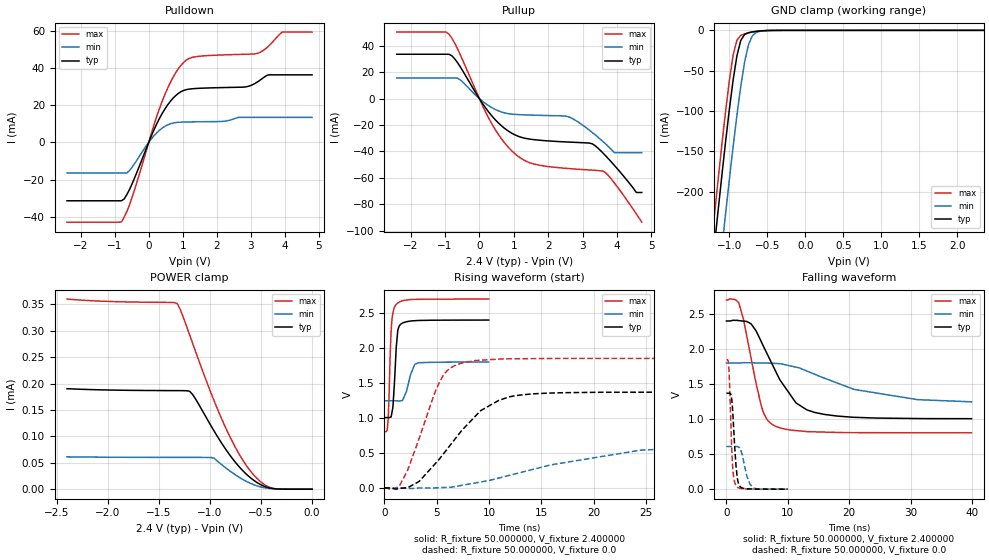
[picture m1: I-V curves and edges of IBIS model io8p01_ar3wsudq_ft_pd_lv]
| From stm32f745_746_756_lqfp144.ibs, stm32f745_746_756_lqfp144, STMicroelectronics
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|   Model io8p01_ar3wsudq_ft_pd_lv
[Model]  io8p01_ar3wsudq_ft_pd_lv
Model_type I/O
Polarity   Non-Inverting
Enable   Active-Low
Vinl =   0.720000V
Vinh =   1.680000V
Vmeas =  1.200000V
Cref =   50.000000pF
Rref =   100.000000M
Vref =   0.0V
C_comp   3.720900pF   3.684200pF   3.822900pF
[Temperature Range]   25.000000   0.125000k   -40.000000
[Pullup Reference]   2.400000V   1.800000V   2.700000V
[Pulldown Reference]   0.0V   0.0V   0.0V
[POWER Clamp Reference]   2.400000V   1.800000V   2.700000V
[GND Clamp Reference]   0.0V   0.0V   0.0V
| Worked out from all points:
|   slope of the pulldown table from 0 to 0.36 V, typ, clamps not added: 25 ohm
|   slope of the pullup table from 0 to 0.36 V, typ, clamps not added: 27.7 ohm
|   GND clamp passes 1 mA (typ) near -0.62 V on its own axis
|   rising waveform, R_fixture 50.000000, V_fixture 2.400000: 20-80 % time 332ps typ, 645ps min, 264ps max; typ from 1 V to 2.4 V
|   rising waveform, R_fixture 50.000000, V_fixture 0.0: 20-80 % time 4.73ns typ, 11.9ns min, 2.67ns max; typ from 0 V to 1.37 V
|   falling waveform, R_fixture 50.000000, V_fixture 2.400000: 20-80 % time 5.31ns typ, 12.5ns min, 2.7ns max; typ from 2.4 V to 1 V
|   falling waveform, R_fixture 50.000000, V_fixture 0.0: 20-80 % time 592ps typ, 1.02ns min, 460ps max; typ from 1.37 V to 0 V
[Pulldown]
|Voltage   I(typ)   I(min)   I(max)
-2.4V     -31.47mA   -16.45mA   -43.01mA
-800mV    -31.47mA   -16.45mA   -42.85mA
-480mV    -21.98mA   -13.17mA   -29.2mA
80mV      3.63mA     1.966mA    5.014mA
480mV     18.15mA    8.738mA    26.02mA
800mV     25.38mA    10.72mA    37.77mA
1.12V     28.53mA    11.02mA    44.6mA
2.8V      29.84mA    13.51mA    47.53mA
3.2V      32.66mA    13.51mA    48.04mA
3.52V     36.44mA    13.51mA    51.84mA
3.92V     36.44mA    13.51mA    59.49mA
4.8V      36.44mA    13.51mA    59.49mA
[Pullup]
|Voltage   I(typ)   I(min)   I(max)
-2.4V     33.58mA    15.57mA    50.36mA
-960mV    33.58mA    15.57mA    50.36mA
-560mV    24.28mA    14.31mA    33.53mA
320mV     -11.75mA   -6.207mA   -17.08mA
960mV     -26.47mA   -11.82mA   -40.02mA
1.52V     -30.88mA   -12.51mA   -49.05mA
2.56V     -32.88mA   -13.52mA   -52.9mA
3.28V     -34.25mA   -25.64mA   -54.18mA
3.6V      -41.44mA   -32.74mA   -55.03mA
3.92V     -50.46mA   -40.9mA    -63.79mA
4.56V     -71.1mA    -40.9mA    -87.27mA
4.72V     -71.1mA    -40.9mA    -93.6mA
[GND_clamp]
|Voltage   I(typ)   I(min)   I(max)
-2.4V     -1.429A    -1.514A    -1.399A
-1.25V    -315.9mA   -407.2mA   -278.2mA
-1.2V     -270.1mA   -361.3mA   -232.1mA
-1.15V    -225mA     -316mA     -186.8mA
-1.1V     -180.9mA   -271.3mA   -142.7mA
-1.05V    -138.2mA   -227.5mA   -100.5mA
-950mV    -61.14mA   -143.6mA   -30.44mA
-900mV    -31.24mA   -104.7mA   -12.15mA
-850mV    -12.5mA    -69.41mA   -6.236mA
-750mV    -2.91mA    -18.35mA   -3.195mA
-600mV    -761.5uA   -1.227mA   -751.9uA
2.35V     58.09uA    37.93uA    67.25uA
[POWER_clamp]
|Voltage   I(typ)   I(min)   I(max)
-2.4V     190.2uA    61.19uA    359.9uA
-1.32V    186.6uA    60.14uA    351.2uA
-1.29V    186.5uA    60.13uA    339.6uA
-1.2V     185.4uA    60.11uA    292.6uA
-1.17V    179.2uA    60.11uA    276.3uA
-960mV    110.2uA    58.62uA    167.5uA
-870mV    82.44uA    43.99uA    126.3uA
-750mV    50.58uA    26.92uA    78.64uA
-630mV    25.94uA    13.41uA    41.02uA
-510mV    9.22uA     4.527uA    14.97uA
-420mV    2.425uA    1.38uA     3.75uA
0V        0A         0A         0A
[Ramp]
| variable   typ   min   max
dV/dt_r  0.82164/4.72408n   0.36480/11.89880n   1.11048/2.66440n
dV/dt_f  0.83676/5.31772n   0.32370/13.40985n   1.13680/2.70151n
R_load = 50.000000
[Rising Waveform]
R_fixture= 50.000000
V_fixture= 2.400000
V_fixture_min= 1.800000
V_fixture_max= 2.700000
|time   V(typ)   V(min)   V(max)
0s        1.005V     1.245V     804.3mV
340.3ps   1.005V     1.245V     950.4mV
640.6ps   1.018V     1.246V     2.26V
820.8ps   1.187V     1.246V     2.509V
1.081ns   1.882V     1.245V     2.616V
1.281ns   2.258V     1.245V     2.644V
1.802ns   2.361V     1.277V     2.678V
2.883ns   2.389V     1.762V     2.694V
3.263ns   2.393V     1.79V      2.695V
9.97ns    2.399V     1.799V     2.699V
[Rising Waveform]
R_fixture= 50.000000
V_fixture= 0.0
V_fixture_min= 0.0
V_fixture_max= 0.0
|time   V(typ)   V(min)   V(max)
0s        177.8uV    72.94uV    448.7uV
1.522ns   -4.552mV   139.8uV    54.49mV
3.283ns   91.27mV    -1.145mV   692.9mV
5.205ns   404.8mV    3.699mV    1.495V
6.086ns   573mV      9.565mV    1.687V
7.367ns   817.9mV    37.03mV    1.783V
9.209ns   1.105V     85.57mV    1.825V
13.13ns   1.33V      225.2mV    1.847V
24.5ns    1.368V     540.2mV    1.851V
39.88ns   1.369V     608.4mV    1.851V
[Falling Waveform]
R_fixture= 50.000000
V_fixture= 2.400000
V_fixture_min= 1.800000
V_fixture_max= 2.700000
|time   V(typ)   V(min)   V(max)
0s        2.399V     1.799V     2.699V
2.002ns   2.405V     1.8V       2.661V
2.803ns   2.397V     1.804V     2.409V
4.004ns   2.359V     1.803V     1.873V
5.846ns   2.07V      1.798V     1.137V
7.768ns   1.724V     1.794V     907.1mV
11.29ns   1.234V     1.741V     835.8mV
14.33ns   1.095V     1.64V      817.7mV
20.82ns   1.025V     1.422V     806.7mV
39.88ns   1.005V     1.245V     804.3mV
[Falling Waveform]
R_fixture= 50.000000
V_fixture= 0.0
V_fixture_min= 0.0
V_fixture_max= 0.0
|time   V(typ)   V(min)   V(max)
0s        1.369V     608.4mV    1.851V
380.4ps   1.369V     608.4mV    1.735V
880.9ps   1.272V     608.2mV    540.9mV
1.121ns   954mV      607.9mV    208mV
1.481ns   427.8mV    608.6mV    63.82mV
1.762ns   164.3mV    608.4mV    30.4mV
2.122ns   49.87mV    592.3mV    14.87mV
3.323ns   5.318mV    185.8mV    2.808mV
4.505ns   1.963mV    13.35mV    1.375mV
9.97ns    177.8uV    72.94uV    448.7uV
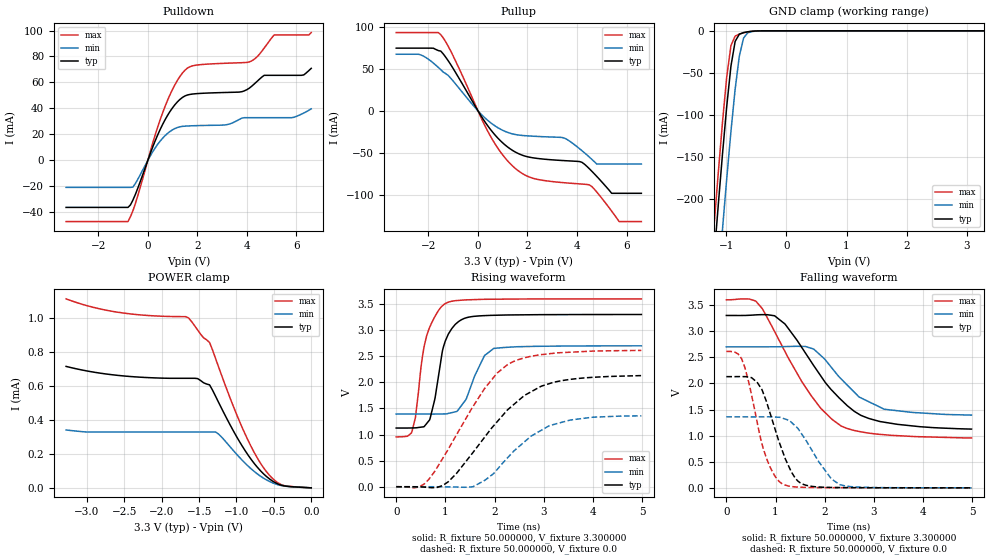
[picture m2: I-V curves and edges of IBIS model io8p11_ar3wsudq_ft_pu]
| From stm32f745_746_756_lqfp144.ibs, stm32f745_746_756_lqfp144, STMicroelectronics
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|   Model io8p11_ar3wsudq_ft_pu
[Model]  io8p11_ar3wsudq_ft_pu
Model_type I/O
Polarity   Non-Inverting
Enable   Active-Low
Vinl =   0.990000V
Vinh =   2.310000V
Vmeas =  1.650000V
Cref =   30.000000pF
Rref =   100.000000M
Vref =   0.0V
C_comp   3.843200pF   3.761700pF   3.937000pF
[Temperature Range]   25.000000   0.125000k   -40.000000
[Pullup Reference]   3.300000V   2.700000V   3.600000V
[Pulldown Reference]   0.0V   0.0V   0.0V
[POWER Clamp Reference]   3.300000V   2.700000V   3.600000V
[GND Clamp Reference]   0.0V   0.0V   0.0V
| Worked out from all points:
|   slope of the pulldown table from 0 to 0.495 V, typ, clamps not added: 20.9 ohm
|   slope of the pullup table from 0 to 0.495 V, typ, clamps not added: 22.6 ohm
|   GND clamp passes 1 mA (typ) near -0.62 V on its own axis
|   rising waveform, R_fixture 50.000000, V_fixture 3.300000: 20-80 % time 277ps typ, 352ps min, 277ps max; typ from 1.12 V to 3.3 V
|   rising waveform, R_fixture 50.000000, V_fixture 0.0: 20-80 % time 1.18ns typ, 961ps min, 1.04ns max; typ from 0.001 V to 2.13 V
|   falling waveform, R_fixture 50.000000, V_fixture 3.300000: 20-80 % time 1.07ns typ, 863ps min, 1.02ns max; typ from 3.3 V to 1.12 V
|   falling waveform, R_fixture 50.000000, V_fixture 0.0: 20-80 % time 466ps typ, 565ps min, 398ps max; typ from 2.13 V to 0.001 V
[Pulldown]
|Voltage   I(typ)   I(min)   I(max)
-3.3V     -36.18mA   -20.77mA   -47.07mA
-800mV    -36.18mA   -20.77mA   -47.07mA
-600mV    -30.5mA    -20.52mA   -38.69mA
700mV     31.4mA     19.11mA    41.71mA
1.2V      45.15mA    25.37mA    61.75mA
1.6V      50.35mA    26.5mA     71.06mA
3.1V      52.28mA    27.26mA    74.76mA
4.1V      55.65mA    32.89mA    75.79mA
4.7V      65.5mA     32.89mA    86.49mA
5.1V      65.5mA     32.89mA    96.55mA
6.3V      65.83mA    36.49mA    96.55mA
6.6V      70.88mA    39.7mA     98.4mA
[Pullup]
|Voltage   I(typ)   I(min)   I(max)
-3.3V     74.71mA    67.42mA    93.28mA
-2.3V     74.71mA    66.58mA    93.28mA
-1.5V     71.15mA    49mA       90.77mA
-1V       50.42mA    35.45mA    65.35mA
500mV     -22.06mA   -14mA      -30.03mA
1.6V      -50.64mA   -28.81mA   -70.96mA
3.5V      -59.52mA   -32.72mA   -85.91mA
4.5V      -69.2mA    -55.26mA   -88.43mA
4.8V      -78.36mA   -63.6mA    -97mA
5.4V      -98.5mA    -63.6mA    -119.7mA
5.7V      -98.5mA    -63.6mA    -132.2mA
6.6V      -98.5mA    -63.6mA    -132.2mA
[GND_clamp]
|Voltage   I(typ)   I(min)   I(max)
-3.3V     -2.325A    -2.404A    -2.299A
-1.2V     -270.2mA   -361.4mA   -232.1mA
-1.13V    -207.3mA   -298.1mA   -169mA
-1.06V    -146.7mA   -236.2mA   -108.8mA
-990mV    -90.18mA   -176.4mA   -54.96mA
-920mV    -42.21mA   -120mA     -17.68mA
-850mV    -12.57mA   -69.47mA   -6.265mA
-780mV    -3.971mA   -30.01mA   -3.886mA
-710mV    -2.1mA     -8.615mA   -2.382mA
-640mV    -1.148mA   -2.283mA   -1.22mA
-570mV    -524uA     -821.5uA   -476.8uA
3.28V     0A         0A         0A
[POWER_clamp]
|Voltage   I(typ)   I(min)   I(max)
-3.28V    715.1uA    340.8uA    1.113mA
-2.6V     662.9uA    328.8uA    1.035mA
-1.64V    645uA      328.8uA    1mA
-1.52V    643.3uA    328.8uA    929.5uA
-1.36V    606.3uA    328.8uA    855.6uA
-1.24V    503.7uA    316.8uA    712.3uA
-960mV    272.5uA    179.4uA    391.9uA
-800mV    165.1uA    110.4uA    239.2uA
-640mV    83.2uA     57.57uA    119.3uA
-520mV    40.52uA    29.83uA    56.09uA
-400mV    15.54uA    13.29uA    18.7uA
0V        0A         0A         0A
[Ramp]
| variable   typ   min   max
dV/dt_r  1.25875/1.16604n   0.80019/0.94572n   1.56010/1.04197n
dV/dt_f  1.27428/1.04940n   0.76752/0.84517n   1.56854/1.01586n
R_load = 50.000000
[Rising Waveform]
R_fixture= 50.000000
V_fixture= 3.300000
V_fixture_min= 2.700000
V_fixture_max= 3.600000
|time   V(typ)   V(min)   V(max)
0s        1.125V     1.393V     955.6mV
320.3ps   1.127V     1.393V     1.057V
390.4ps   1.129V     1.393V     1.326V
560.6ps   1.149V     1.393V     2.647V
680.7ps   1.283V     1.393V     3.056V
1.011ns   2.82V      1.396V     3.515V
1.421ns   3.236V     1.676V     3.58V
1.792ns   3.278V     2.507V     3.591V
1.982ns   3.284V     2.649V     3.592V
4.985ns   3.3V       2.7V       3.599V
[Rising Waveform]
R_fixture= 50.000000
V_fixture= 0.0
V_fixture_min= 0.0
V_fixture_max= 0.0
|time   V(typ)   V(min)   V(max)
0s        1.433mV    1.239mV    1.787mV
570.6ps   -6.138mV   1.229mV    54.34mV
840.8ps   -9.86mV    894.5uV    382.8mV
1.061ns   98.44mV    -1.345mV   725.5mV
1.562ns   658.1mV    1.247mV    1.537V
2.052ns   1.246V     330.3mV    2.178V
2.352ns   1.545V     645mV      2.385V
3.113ns   1.976V     1.17V      2.548V
3.994ns   2.097V     1.333V     2.599V
4.985ns   2.129V     1.359V     2.612V
[Falling Waveform]
R_fixture= 50.000000
V_fixture= 3.300000
V_fixture_min= 2.700000
V_fixture_max= 3.600000
|time   V(typ)   V(min)   V(max)
0s        3.3V       2.7V       3.599V
600.6ps   3.311V     2.7V       3.573V
740.7ps   3.316V     2.7V       3.416V
981ps     3.294V     2.701V     2.994V
1.201ns   3.126V     2.704V     2.594V
1.772ns   2.347V     2.659V     1.708V
2.332ns   1.688V     2.088V     1.186V
2.703ns   1.407V     1.738V     1.08V
3.213ns   1.257V     1.505V     1.017V
4.985ns   1.125V     1.393V     955.6mV
[Falling Waveform]
R_fixture= 50.000000
V_fixture= 0.0
V_fixture_min= 0.0
V_fixture_max= 0.0
|time   V(typ)   V(min)   V(max)
0s        2.129V     1.359V     2.612V
310.3ps   2.13V      1.359V     2.473V
470.5ps   2.117V     1.359V     1.965V
630.6ps   2.016V     1.359V     1.24V
880.9ps   1.456V     1.36V      416mV
1.131ns   731.6mV    1.339V     83.11mV
1.502ns   97.45mV    1.075V     13.98mV
2.132ns   8.951mV    176.6mV    4.432mV
2.312ns   6.693mV    61.01mV    4.047mV
4.985ns   1.433mV    1.239mV    1.787mV
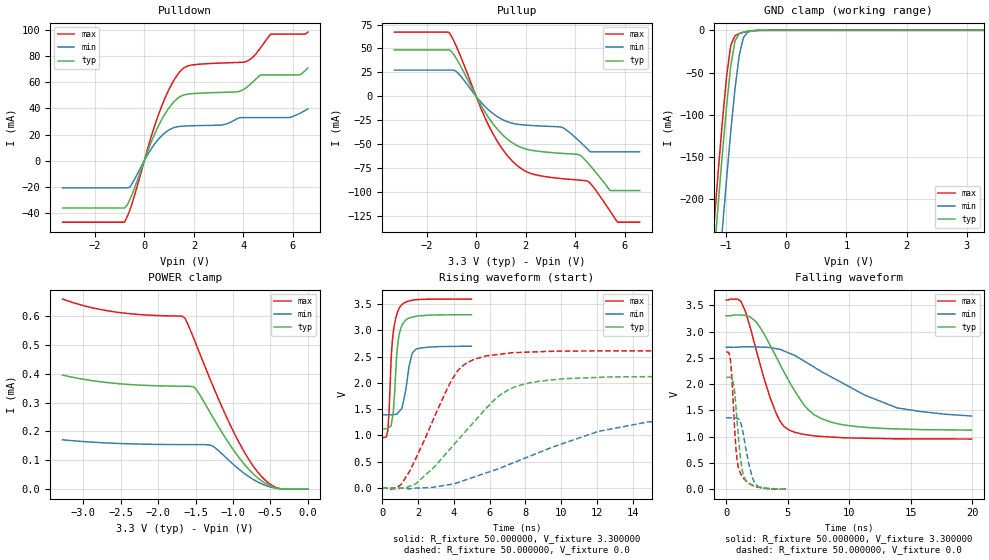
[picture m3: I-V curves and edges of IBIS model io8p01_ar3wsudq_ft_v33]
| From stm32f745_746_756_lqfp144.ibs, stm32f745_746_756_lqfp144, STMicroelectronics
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|   Model io8p01_ar3wsudq_ft_v33
[Model]  io8p01_ar3wsudq_ft_v33
Model_type I/O
Polarity   Non-Inverting
Enable   Active-Low
Vinl =   0.990000V
Vinh =   2.310000V
Vmeas =  1.650000V
Cref =   50.000000pF
Rref =   100.000000M
Vref =   0.0V
C_comp   3.857500pF   3.760500pF   3.941700pF
[Temperature Range]   25.000000   0.125000k   -40.000000
[Pullup Reference]   3.300000V   2.700000V   3.600000V
[Pulldown Reference]   0.0V   0.0V   0.0V
[POWER Clamp Reference]   3.300000V   2.700000V   3.600000V
[GND Clamp Reference]   0.0V   0.0V   0.0V
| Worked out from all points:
|   slope of the pulldown table from 0 to 0.495 V, typ, clamps not added: 20.9 ohm
|   slope of the pullup table from 0 to 0.495 V, typ, clamps not added: 22.6 ohm
|   GND clamp passes 1 mA (typ) near -0.62 V on its own axis
|   rising waveform, R_fixture 50.000000, V_fixture 3.300000: 20-80 % time 277ps typ, 398ps min, 275ps max; typ from 1.12 V to 3.3 V
|   rising waveform, R_fixture 50.000000, V_fixture 0.0: 20-80 % time 3.36ns typ, 6.53ns min, 2.12ns max; typ from 0 V to 2.13 V
|   falling waveform, R_fixture 50.000000, V_fixture 3.300000: 20-80 % time 3.2ns typ, 6.4ns min, 2.04ns max; typ from 3.3 V to 1.12 V
|   falling waveform, R_fixture 50.000000, V_fixture 0.0: 20-80 % time 516ps typ, 710ps min, 443ps max; typ from 2.13 V to 0 V
[Pulldown]
|Voltage   I(typ)   I(min)   I(max)
-3.3V     -36.18mA   -20.77mA   -47.07mA
-800mV    -36.18mA   -20.77mA   -47.07mA
-600mV    -30.5mA    -20.52mA   -38.69mA
700mV     31.4mA     19.11mA    41.71mA
1.2V      45.15mA    25.37mA    61.75mA
1.6V      50.35mA    26.5mA     71.06mA
3.1V      52.28mA    27.26mA    74.76mA
4.1V      55.7mA     32.99mA    75.8mA
4.7V      65.72mA    32.99mA    86.64mA
5.1V      65.72mA    32.99mA    96.89mA
6.3V      65.85mA    36.5mA     96.89mA
6.6V      70.91mA    39.71mA    98.45mA
[Pullup]
|Voltage   I(typ)   I(min)   I(max)
-3.3V     48.51mA    27.44mA    67.09mA
-1.1V     48.51mA    27.44mA    66.83mA
-700mV    35.13mA    23.48mA    46.33mA
500mV     -22.07mA   -14mA      -30.03mA
1.5V      -49.1mA    -28.3mA    -68.56mA
2.2V      -56.05mA   -30.32mA   -80.35mA
3.5V      -59.53mA   -32.72mA   -85.92mA
4.2V      -61.52mA   -47.6mA    -87.46mA
4.5V      -69.21mA   -55.15mA   -88.43mA
5.4V      -98.3mA    -57.9mA    -119.4mA
5.7V      -98.3mA    -57.9mA    -131.3mA
6.6V      -98.3mA    -57.9mA    -131.3mA
[GND_clamp]
|Voltage   I(typ)   I(min)   I(max)
-3.3V     -2.333A    -2.407A    -2.313A
-1.2V     -270.2mA   -361.4mA   -232.1mA
-1.13V    -207.3mA   -298.1mA   -169mA
-1.06V    -146.7mA   -236.2mA   -108.8mA
-990mV    -90.18mA   -176.4mA   -54.96mA
-920mV    -42.21mA   -120mA     -17.68mA
-850mV    -12.57mA   -69.47mA   -6.265mA
-780mV    -3.971mA   -30.01mA   -3.886mA
-710mV    -2.1mA     -8.615mA   -2.382mA
-640mV    -1.148mA   -2.283mA   -1.22mA
-570mV    -524uA     -821.5uA   -476.8uA
3.28V     0A         0A         0A
[POWER_clamp]
|Voltage   I(typ)   I(min)   I(max)
-3.28V    395.3uA    171.3uA    658.7uA
-2.6V     367.1uA    159uA      614.9uA
-1.68V    356.7uA    154.4uA    599.4uA
-1.64V    356.5uA    154.4uA    590.8uA
-1.52V    353.6uA    154.3uA    518.3uA
-1.48V    341.1uA    154.2uA    492.3uA
-1.28V    253.6uA    150.4uA    364.2uA
-960mV    123.1uA    77.55uA    181.6uA
-720mV    50.52uA    32.03uA    76.18uA
-560mV    18.94uA    12.27uA    28.65uA
-440mV    5.104uA    3.69uA     7.327uA
0V        0A         0A         0A
[Ramp]
| variable   typ   min   max
dV/dt_r  1.27764/3.35565n   0.80076/6.63242n   1.56720/2.11409n
dV/dt_f  1.30260/3.20700n   0.74268/6.39481n   1.58788/2.03530n
R_load = 50.000000
[Rising Waveform]
R_fixture= 50.000000
V_fixture= 3.300000
V_fixture_min= 2.700000
V_fixture_max= 3.600000
|time   V(typ)   V(min)   V(max)
0s        1.124V     1.392V     954.2mV
320.3ps   1.132V     1.392V     1.099V
390.4ps   1.151V     1.391V     1.455V
510.5ps   1.2V       1.392V     2.477V
650.7ps   1.577V     1.398V     3.035V
830.8ps   2.594V     1.409V     3.315V
991ps     2.979V     1.471V     3.448V
1.682ns   3.255V     2.57V      3.576V
1.882ns   3.269V     2.642V     3.587V
4.985ns   3.3V       2.7V       3.599V
[Rising Waveform]
R_fixture= 50.000000
V_fixture= 0.0
V_fixture_min= 0.0
V_fixture_max= 0.0
|time   V(typ)   V(min)   V(max)
0s        196.4uV    83.4uV     722.1uV
1.041ns   -10.14mV   -4.317mV   56.18mV
1.882ns   78.86mV    -5.015mV   561.1mV
3.844ns   759.6mV    67.51mV    2.031V
5.085ns   1.241V     200.2mV    2.443V
6.567ns   1.765V     373.5mV    2.547V
8.208ns   1.999V     598.4mV    2.588V
12.05ns   2.105V     1.075V     2.61V
14.77ns   2.12V      1.252V     2.612V
19.94ns   2.129V     1.359V     2.612V
[Falling Waveform]
R_fixture= 50.000000
V_fixture= 3.300000
V_fixture_min= 2.700000
V_fixture_max= 3.600000
|time   V(typ)   V(min)   V(max)
0s        3.3V       2.7V       3.599V
1.201ns   3.314V     2.708V     3.573V
2.442ns   3.185V     2.707V     2.647V
3.604ns   2.725V     2.691V     1.723V
4.324ns   2.401V     2.664V     1.315V
5.085ns   2.066V     2.593V     1.131V
6.727ns   1.501V     2.382V     1.029V
8.569ns   1.273V     2.132V     991.8mV
13.89ns   1.147V     1.547V     958.7mV
19.94ns   1.124V     1.392V     954.2mV
[Falling Waveform]
R_fixture= 50.000000
V_fixture= 0.0
V_fixture_min= 0.0
V_fixture_max= 0.0
|time   V(typ)   V(min)   V(max)
0s        2.129V     1.359V     2.612V
340.3ps   2.126V     1.358V     2.474V
500.5ps   2.082V     1.358V     1.97V
640.6ps   1.941V     1.358V     1.363V
890.9ps   1.294V     1.347V     553mV
1.171ns   578.9mV    1.262V     295.9mV
1.512ns   205.7mV    893.9mV    182.2mV
1.852ns   108.4mV    473.4mV    112.1mV
2.312ns   59.63mV    121.3mV    51.33mV
4.985ns   196.4uV    83.4uV     722.1uV
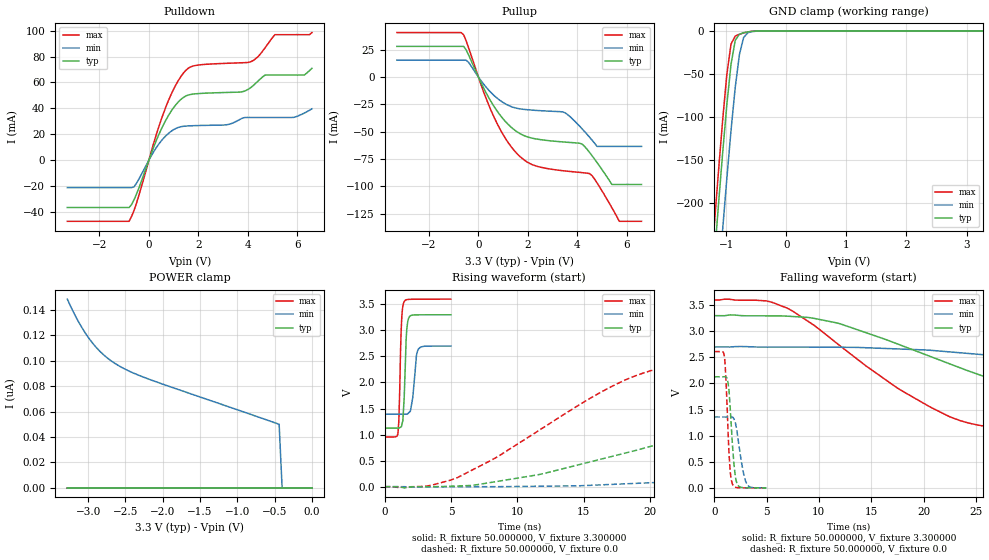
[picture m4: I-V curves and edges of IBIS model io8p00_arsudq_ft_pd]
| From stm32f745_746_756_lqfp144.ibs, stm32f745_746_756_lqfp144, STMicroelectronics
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|   Model io8p00_arsudq_ft_pd
[Model]  io8p00_arsudq_ft_pd
Model_type I/O
Polarity   Non-Inverting
Enable   Active-Low
Vinl =   0.990000V
Vinh =   2.310000V
Vmeas =  1.650000V
Cref =   50.000000pF
Rref =   100.000000M
Vref =   0.0V
C_comp   2.292100pF   2.228000pF   2.366600pF
[Temperature Range]   25.000000   0.125000k   -40.000000
[Pullup Reference]   3.300000V   2.700000V   3.600000V
[Pulldown Reference]   0.0V   0.0V   0.0V
[POWER Clamp Reference]   3.300000V   2.700000V   3.600000V
[GND Clamp Reference]   0.0V   0.0V   0.0V
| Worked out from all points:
|   slope of the pulldown table from 0 to 0.495 V, typ, clamps not added: 20.9 ohm
|   slope of the pullup table from 0 to 0.495 V, typ, clamps not added: 22.6 ohm
|   GND clamp passes 1 mA (typ) near -0.62 V on its own axis
|   rising waveform, R_fixture 50.000000, V_fixture 3.300000: 20-80 % time 190ps typ, 291ps min, 164ps max; typ from 1.12 V to 3.3 V
|   rising waveform, R_fixture 50.000000, V_fixture 0.0: 20-80 % time 19.7ns typ, 51ns min, 10.4ns max; typ from 0 V to 2.13 V
|   falling waveform, R_fixture 50.000000, V_fixture 3.300000: 20-80 % time 18.7ns typ, 39.7ns min, 11.5ns max; typ from 3.3 V to 1.12 V
|   falling waveform, R_fixture 50.000000, V_fixture 0.0: 20-80 % time 433ps typ, 632ps min, 343ps max; typ from 2.13 V to 0 V
[Pulldown]
|Voltage   I(typ)   I(min)   I(max)
-3.3V     -36.46mA   -21.1mA    -47.09mA
-800mV    -36.46mA   -21.1mA    -47.09mA
-600mV    -30.5mA    -20.54mA   -38.69mA
700mV     31.4mA     19.11mA    41.71mA
1.2V      45.15mA    25.37mA    61.75mA
1.6V      50.35mA    26.5mA     71.06mA
3.1V      52.27mA    27.26mA    74.75mA
4.1V      55.7mA     32.99mA    75.8mA
4.7V      65.72mA    32.99mA    86.69mA
5.1V      65.72mA    32.99mA    96.9mA
6.3V      65.87mA    36.5mA     96.9mA
6.6V      70.93mA    39.71mA    98.5mA
[Pullup]
|Voltage   I(typ)   I(min)   I(max)
-3.3V     28.03mA    15.43mA    40.69mA
-700mV    28.03mA    15.43mA    40.69mA
-400mV    20.31mA    13.47mA    26.93mA
600mV     -25.77mA   -16.23mA   -35.13mA
1.6V      -50.64mA   -28.81mA   -70.96mA
3.5V      -59.53mA   -32.65mA   -85.92mA
4.2V      -61.43mA   -47.49mA   -87.46mA
4.5V      -69.06mA   -55.12mA   -88.38mA
4.8V      -78.23mA   -63.5mA    -96.83mA
5.4V      -98.3mA    -63.5mA    -119.6mA
5.7V      -98.3mA    -63.5mA    -132mA
6.6V      -98.3mA    -63.5mA    -132mA
[GND_clamp]
|Voltage   I(typ)   I(min)   I(max)
-3.3V     -2.318A    -2.397A    -2.291A
-1.2V     -265.5mA   -356.1mA   -227.2mA
-1.13V    -202.7mA   -292.9mA   -164.1mA
-1.06V    -142.2mA   -231.2mA   -104.1mA
-990mV    -85.98mA   -171.6mA   -50.73mA
-920mV    -38.81mA   -115.5mA   -15.29mA
-850mV    -11.09mA   -65.61mA   -6.016mA
-780mV    -3.793mA   -27.42mA   -3.89mA
-710mV    -2.098mA   -7.698mA   -2.396mA
-640mV    -1.159mA   -2.127mA   -1.234mA
-570mV    -535.1uA   -807.4uA   -490.2uA
3.28V     81.28uA    57.87uA    93.98uA
[POWER_clamp]
|Voltage   I(typ)   I(min)   I(max)
-3.28V    0A         148.5nA    0A
-3.2V     0A         138.6nA    0A
-3.12V    0A         129.7nA    0A
-3.04V    0A         122nA      0A
-2.96V    0A         115.3nA    0A
-2.8V     0A         105.1nA    0A
-2.6V     0A         96.44nA    0A
-2.4V     0A         90.52nA    0A
-2.16V    0A         84.97nA    0A
-440mV    0A         50.04nA    0A
-400mV    0A         0A         0A
0V        0A         0A         0A
[Ramp]
| variable   typ   min   max
dV/dt_r  1.27668/19.69888n   0.81474/51.01036n   1.56654/10.33703n
dV/dt_f  1.30626/18.72002n   0.78504/39.74867n   1.58742/11.43997n
R_load = 50.000000
[Rising Waveform]
R_fixture= 50.000000
V_fixture= 3.300000
V_fixture_min= 2.700000
V_fixture_max= 3.600000
|time   V(typ)   V(min)   V(max)
0s        1.123V     1.39V      953.1mV
1.001ns   1.125V     1.391V     1.018V
1.071ns   1.127V     1.391V     1.288V
1.251ns   1.148V     1.391V     3.036V
1.461ns   1.66V      1.389V     3.544V
1.632ns   2.883V     1.392V     3.587V
1.862ns   3.26V      1.429V     3.595V
2.112ns   3.293V     1.702V     3.596V
2.533ns   3.297V     2.64V      3.597V
4.985ns   3.299V     2.699V     3.599V
[Rising Waveform]
R_fixture= 50.000000
V_fixture= 0.0
V_fixture_min= 0.0
V_fixture_max= 0.0
|time   V(typ)   V(min)   V(max)
0s        4.821nV    241.3nV    3.051nV
5.506ns   13.81mV    -140.1uV   177.6mV
11.51ns   227.3mV    8.249mV    1.063V
19.02ns   703.2mV    64.82mV    2.14V
27.53ns   1.298V     163.3mV    2.486V
38.54ns   1.853V     359.9mV    2.575V
57.56ns   2.067V     709.4mV    2.607V
89.09ns   2.118V     1.138V     2.611V
117.6ns   2.127V     1.297V     2.611V
249.2ns   2.128V     1.358V     2.611V
[Falling Waveform]
R_fixture= 50.000000
V_fixture= 3.300000
V_fixture_min= 2.700000
V_fixture_max= 3.600000
|time   V(typ)   V(min)   V(max)
0s        3.299V     2.699V     3.599V
5.506ns   3.295V     2.697V     3.556V
12.01ns   3.144V     2.693V     2.722V
22.52ns   2.374V     2.604V     1.36V
31.53ns   1.731V     2.431V     1.073V
39.54ns   1.388V     2.238V     1.016V
47.05ns   1.269V     2.052V     996.2mV
62.56ns   1.185V     1.738V     969.4mV
90.59ns   1.142V     1.509V     955.7mV
249.2ns   1.123V     1.39V      953.1mV
[Falling Waveform]
R_fixture= 50.000000
V_fixture= 0.0
V_fixture_min= 0.0
V_fixture_max= 0.0
|time   V(typ)   V(min)   V(max)
0s        2.128V     1.358V     2.611V
981ps     2.129V     1.357V     2.506V
1.151ns   2.119V     1.357V     1.945V
1.411ns   1.869V     1.358V     683.7mV
1.542ns   1.488V     1.36V      294.8mV
1.742ns   830.7mV    1.353V     75.43mV
2.152ns   98.77mV    1.119V     6.562mV
2.833ns   3.156mV    244.5mV    111.1uV
3.123ns   849.3uV    72.11mV    77.11uV
4.985ns   4.821nV    241.3nV    3.051nV
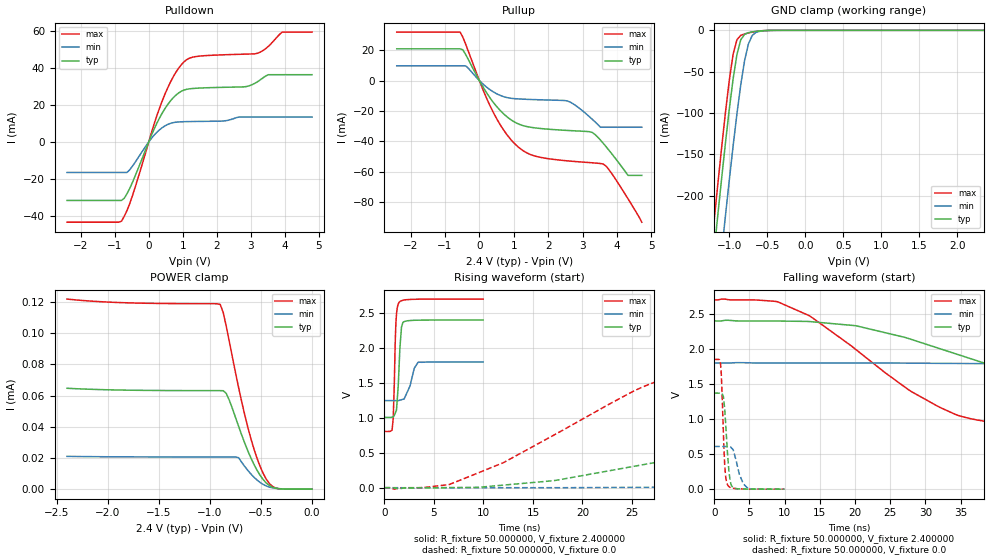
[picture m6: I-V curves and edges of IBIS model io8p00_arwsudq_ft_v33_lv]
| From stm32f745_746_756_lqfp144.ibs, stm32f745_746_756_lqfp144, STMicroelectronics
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|   Model io8p00_arwsudq_ft_v33_lv
[Model]  io8p00_arwsudq_ft_v33_lv
Model_type I/O
Polarity   Non-Inverting
Enable   Active-Low
Vinl =   0.720000V
Vinh =   1.680000V
Vmeas =  1.200000V
Cref =   50.000000pF
Rref =   100.000000M
Vref =   0.0V
C_comp   2.828400pF   2.771400pF   2.910300pF
[Temperature Range]   25.000000   0.125000k   -40.000000
[Pullup Reference]   2.400000V   1.800000V   2.700000V
[Pulldown Reference]   0.0V   0.0V   0.0V
[POWER Clamp Reference]   2.400000V   1.800000V   2.700000V
[GND Clamp Reference]   0.0V   0.0V   0.0V
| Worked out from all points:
|   slope of the pulldown table from 0 to 0.36 V, typ, clamps not added: 25 ohm
|   slope of the pullup table from 0 to 0.36 V, typ, clamps not added: 27.7 ohm
|   GND clamp passes 1 mA (typ) near -0.62 V on its own axis
|   rising waveform, R_fixture 50.000000, V_fixture 2.400000: 20-80 % time 323ps typ, 710ps min, 219ps max; typ from 1.01 V to 2.4 V
|   rising waveform, R_fixture 50.000000, V_fixture 0.0: 20-80 % time 30.9ns typ, 81.7ns min, 14.6ns max; typ from 0 V to 1.37 V
|   falling waveform, R_fixture 50.000000, V_fixture 2.400000: 20-80 % time 28.7ns typ, 81.4ns min, 16.1ns max; typ from 2.4 V to 1.01 V
|   falling waveform, R_fixture 50.000000, V_fixture 0.0: 20-80 % time 552ps typ, 1.05ns min, 408ps max; typ from 1.37 V to 0 V
[Pulldown]
|Voltage   I(typ)   I(min)   I(max)
-2.4V     -31.66mA   -16.51mA   -43.43mA
-800mV    -31.66mA   -16.51mA   -42.86mA
-480mV    -21.98mA   -13.17mA   -29.21mA
80mV      3.63mA     1.966mA    5.014mA
480mV     18.16mA    8.738mA    26.02mA
800mV     25.38mA    10.72mA    37.77mA
1.12V     28.53mA    11.02mA    44.6mA
2.8V      29.84mA    13.48mA    47.53mA
3.2V      32.65mA    13.48mA    48.04mA
3.52V     36.42mA    13.48mA    51.83mA
3.92V     36.42mA    13.48mA    59.49mA
4.8V      36.42mA    13.48mA    59.49mA
[Pullup]
|Voltage   I(typ)   I(min)   I(max)
-2.4V     20.89mA    9.661mA    31.89mA
-560mV    20.89mA    9.661mA    31.89mA
-400mV    17.28mA    9.661mA    24.06mA
320mV     -11.75mA   -6.207mA   -17.08mA
640mV     -20.52mA   -10.1mA    -30.35mA
960mV     -26.47mA   -11.82mA   -40.02mA
1.52V     -30.88mA   -12.51mA   -49.05mA
2.56V     -32.88mA   -13.49mA   -52.9mA
3.28V     -34.2mA    -25.51mA   -54.18mA
3.6V      -41.34mA   -30.77mA   -55mA
4.32V     -62.48mA   -30.77mA   -77.88mA
4.72V     -62.48mA   -30.77mA   -93.3mA
[GND_clamp]
|Voltage   I(typ)   I(min)   I(max)
-2.4V     -1.428A    -1.51A     -1.401A
-1.2V     -266.4mA   -356.3mA   -229.4mA
-1.15V    -221.3mA   -311mA     -184.1mA
-1.1V     -177.3mA   -266.4mA   -140mA
-1.05V    -134.8mA   -222.7mA   -97.97mA
-950mV    -58.22mA   -139.2mA   -28.55mA
-900mV    -29.03mA   -100.6mA   -11.27mA
-850mV    -11.41mA   -65.77mA   -6.067mA
-750mV    -2.852mA   -16.63mA   -3.179mA
-700mV    -1.914mA   -6.318mA   -2.181mA
-600mV    -750uA     -1.167mA   -738.3uA
2.35V     0A         0A         0A
[POWER_clamp]
|Voltage   I(typ)   I(min)   I(max)
-2.4V     64.71uA    21.03uA    121.9uA
-1.86V    63.55uA    20.74uA    119.6uA
-900mV    63.18uA    20.63uA    118.5uA
-870mV    63.14uA    20.63uA    113.2uA
-840mV    61.36uA    20.62uA    104.3uA
-720mV    40.37uA    20.18uA    65.28uA
-630mV    24.69uA    12.08uA    39.85uA
-540mV    12.26uA    5.907uA    20uA
-480mV    6.236uA    3.061uA    10.23uA
-420mV    2.4uA      1.365uA    3.726uA
-360mV    667.9nA    564nA      839.6nA
0V        0A         0A         0A
[Ramp]
| variable   typ   min   max
dV/dt_r  0.82266/30.92402n   0.36307/83.76211n   1.11090/14.58646n
dV/dt_f  0.83694/28.71630n   0.32682/81.64554n   1.13755/16.05883n
R_load = 50.000000
[Rising Waveform]
R_fixture= 50.000000
V_fixture= 2.400000
V_fixture_min= 1.800000
V_fixture_max= 2.700000
|time   V(typ)   V(min)   V(max)
0s        1.006V     1.247V     804.6mV
780.8ps   1.011V     1.247V     844.4mV
880.9ps   1.016V     1.247V     987.1mV
1.161ns   1.092V     1.247V     2.379V
1.381ns   1.445V     1.246V     2.624V
1.481ns   1.756V     1.249V     2.653V
1.722ns   2.3V       1.26V      2.676V
1.882ns   2.369V     1.266V     2.683V
3.403ns   2.398V     1.797V     2.698V
9.97ns    2.4V       1.8V       2.7V
[Rising Waveform]
R_fixture= 50.000000
V_fixture= 0.0
V_fixture_min= 0.0
V_fixture_max= 0.0
|time   V(typ)   V(min)   V(max)
0s        8.272nV    282.4nV    27.65nV
7.007ns   1.535mV    -64.85uV   71.32mV
12.01ns   37.01mV    -29.46uV   358.2mV
17.02ns   99.56mV    85.74uV    746mV
28.03ns   378.1mV    6.611mV    1.545V
40.04ns   717.3mV    32.73mV    1.775V
59.56ns   1.172V     99.1mV     1.834V
79.58ns   1.315V     193.2mV    1.85V
152.7ns   1.369V     509.1mV    1.852V
249.2ns   1.37V      609.1mV    1.852V
[Falling Waveform]
R_fixture= 50.000000
V_fixture= 2.400000
V_fixture_min= 1.800000
V_fixture_max= 2.700000
|time   V(typ)   V(min)   V(max)
0s        2.4V       1.8V       2.7V
9.009ns   2.399V     1.8V       2.674V
13.51ns   2.392V     1.8V       2.475V
20.02ns   2.333V     1.8V       2V
32.03ns   2.005V     1.795V     1.168V
42.54ns   1.66V      1.78V      921.9mV
60.06ns   1.239V     1.72V      844.8mV
87.59ns   1.072V     1.567V     814.5mV
157.2ns   1.014V     1.325V     805mV
249.2ns   1.006V     1.247V     804.6mV
[Falling Waveform]
R_fixture= 50.000000
V_fixture= 0.0
V_fixture_min= 0.0
V_fixture_max= 0.0
|time   V(typ)   V(min)   V(max)
0s        1.37V      609.1mV    1.852V
900.9ps   1.371V     609mV      1.792V
1.101ns   1.367V     608.8mV    1.415V
1.481ns   1.155V     608.6mV    370.1mV
1.922ns   470.8mV    609.7mV    57.86mV
2.262ns   121.1mV    606.7mV    25.63mV
2.743ns   18.75mV    544.4mV    12.29mV
3.584ns   3.783mV    208.8mV    4.735mV
4.805ns   1.334mV    9.709mV    1.503mV
9.97ns    8.272nV    282.4nV    27.65nV
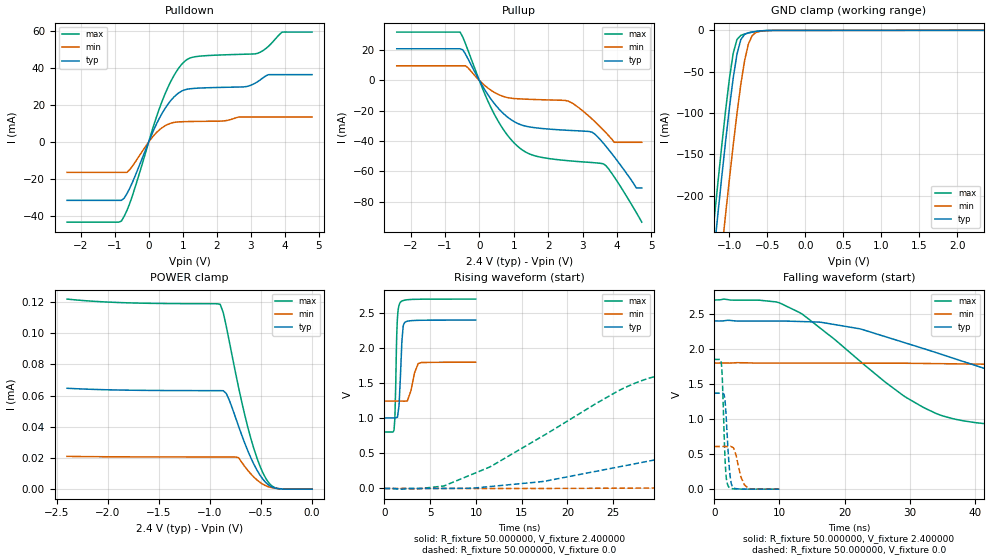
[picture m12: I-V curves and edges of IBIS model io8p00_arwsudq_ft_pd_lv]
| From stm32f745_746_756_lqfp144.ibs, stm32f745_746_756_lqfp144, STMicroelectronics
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|   Model io8p00_arwsudq_ft_pd_lv
[Model]  io8p00_arwsudq_ft_pd_lv
Model_type I/O
Polarity   Non-Inverting
Enable   Active-Low
Vinl =   0.720000V
Vinh =   1.680000V
Vmeas =  1.200000V
Cref =   50.000000pF
Rref =   100.000000M
Vref =   0.0V
C_comp   2.828000pF   2.774600pF   2.917100pF
[Temperature Range]   25.000000   0.125000k   -40.000000
[Pullup Reference]   2.400000V   1.800000V   2.700000V
[Pulldown Reference]   0.0V   0.0V   0.0V
[POWER Clamp Reference]   2.400000V   1.800000V   2.700000V
[GND Clamp Reference]   0.0V   0.0V   0.0V
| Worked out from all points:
|   slope of the pulldown table from 0 to 0.36 V, typ, clamps not added: 25 ohm
|   slope of the pullup table from 0 to 0.36 V, typ, clamps not added: 27.7 ohm
|   GND clamp passes 1 mA (typ) near -0.62 V on its own axis
|   rising waveform, R_fixture 50.000000, V_fixture 2.400000: 20-80 % time 288ps typ, 617ps min, 205ps max; typ from 1 V to 2.4 V
|   rising waveform, R_fixture 50.000000, V_fixture 0.0: 20-80 % time 30.9ns typ, 81ns min, 14.7ns max; typ from 0 V to 1.37 V
|   falling waveform, R_fixture 50.000000, V_fixture 2.400000: 20-80 % time 29.1ns typ, 75.7ns min, 15.8ns max; typ from 2.4 V to 1 V
|   falling waveform, R_fixture 50.000000, V_fixture 0.0: 20-80 % time 541ps typ, 1ns min, 411ps max; typ from 1.37 V to 0 V
[Pulldown]
|Voltage   I(typ)   I(min)   I(max)
-2.4V     -31.67mA   -16.51mA   -43.52mA
-800mV    -31.67mA   -16.51mA   -42.86mA
-480mV    -21.98mA   -13.17mA   -29.21mA
80mV      3.63mA     1.966mA    5.012mA
480mV     18.15mA    8.738mA    26.02mA
800mV     25.38mA    10.72mA    37.77mA
1.12V     28.53mA    11.02mA    44.6mA
2.8V      29.84mA    13.49mA    47.53mA
3.2V      32.65mA    13.49mA    48.03mA
3.52V     36.46mA    13.49mA    51.84mA
3.92V     36.46mA    13.49mA    59.54mA
4.8V      36.46mA    13.49mA    59.54mA
[Pullup]
|Voltage   I(typ)   I(min)   I(max)
-2.4V     20.89mA    9.66mA     31.89mA
-560mV    20.89mA    9.66mA     31.89mA
-400mV    17.28mA    9.66mA     24.06mA
320mV     -11.75mA   -6.207mA   -17.08mA
960mV     -26.47mA   -11.82mA   -40.02mA
1.52V     -30.88mA   -12.51mA   -49.05mA
2.56V     -32.88mA   -13.48mA   -52.9mA
3.28V     -34.2mA    -25.52mA   -54.18mA
3.6V      -41.32mA   -32.62mA   -54.99mA
3.92V     -50.34mA   -40.8mA    -63.66mA
4.56V     -70.9mA    -40.8mA    -87.12mA
4.72V     -70.9mA    -40.8mA    -93.5mA
[GND_clamp]
|Voltage   I(typ)   I(min)   I(max)
-2.4V     -1.425A    -1.509A    -1.395A
-1.25V    -311.8mA   -402mA     -274.5mA
-1.2V     -266mA     -356.2mA   -228.4mA
-1.15V    -220.9mA   -310.9mA   -183.1mA
-1.1V     -176.9mA   -266.3mA   -139mA
-1.05V    -134.3mA   -222.6mA   -97.01mA
-950mV    -57.82mA   -139.1mA   -27.87mA
-900mV    -28.73mA   -100.5mA   -11.05mA
-850mV    -11.3mA    -65.69mA   -6.068mA
-750mV    -2.863mA   -16.61mA   -3.194mA
-600mV    -761.3uA   -1.176mA   -752.1uA
2.35V     58.09uA    37.92uA    67.25uA
[POWER_clamp]
|Voltage   I(typ)   I(min)   I(max)
-2.4V     64.71uA    21.03uA    121.9uA
-1.86V    63.55uA    20.74uA    119.6uA
-900mV    63.18uA    20.63uA    118.5uA
-870mV    63.14uA    20.63uA    113.2uA
-840mV    61.36uA    20.62uA    104.3uA
-720mV    40.37uA    20.18uA    65.28uA
-630mV    24.69uA    12.08uA    39.85uA
-540mV    12.26uA    5.907uA    20uA
-480mV    6.236uA    3.061uA    10.23uA
-420mV    2.4uA      1.365uA    3.726uA
-360mV    667.9nA    564nA      839.6nA
0V        0A         0A         0A
[Ramp]
| variable   typ   min   max
dV/dt_r  0.82152/30.85408n   0.36215/83.25155n   1.11023/14.65210n
dV/dt_f  0.83652/29.09542n   0.32700/76.06151n   1.13689/15.79924n
R_load = 50.000000
[Rising Waveform]
R_fixture= 50.000000
V_fixture= 2.400000
V_fixture_min= 1.800000
V_fixture_max= 2.700000
|time   V(typ)   V(min)   V(max)
0s        1.005V     1.245V     804.2mV
1.041ns   1.005V     1.245V     830.6mV
1.141ns   1.005V     1.246V     1.028V
1.401ns   1.016V     1.246V     2.389V
1.582ns   1.172V     1.246V     2.606V
1.742ns   1.596V     1.246V     2.654V
2.042ns   2.309V     1.245V     2.678V
2.262ns   2.37V      1.244V     2.684V
3.684ns   2.396V     1.78V      2.696V
9.97ns    2.399V     1.799V     2.699V
[Rising Waveform]
R_fixture= 50.000000
V_fixture= 0.0
V_fixture_min= 0.0
V_fixture_max= 0.0
|time   V(typ)   V(min)   V(max)
0s        1.441uV    362.2nV    16.22uV
6.507ns   624uV      -73.87uV   36.3mV
11.51ns   27.26mV    -48.29uV   306.2mV
25.53ns   305.3mV    4.18mV     1.389V
28.53ns   381.1mV    5.782mV    1.555V
40.54ns   738.9mV    34.16mV    1.776V
56.06ns   1.115V     82.66mV    1.831V
79.58ns   1.313V     191.4mV    1.849V
148.1ns   1.367V     493.1mV    1.851V
249.2ns   1.369V     608.5mV    1.851V
[Falling Waveform]
R_fixture= 50.000000
V_fixture= 2.400000
V_fixture_min= 1.800000
V_fixture_max= 2.700000
|time   V(typ)   V(min)   V(max)
0s        2.399V     1.799V     2.699V
10.01ns   2.397V     1.798V     2.657V
13.51ns   2.39V      1.798V     2.496V
22.02ns   2.292V     1.798V     1.852V
32.03ns   2.007V     1.793V     1.168V
44.04ns   1.643V     1.78V      910.2mV
58.06ns   1.27V      1.726V     852.8mV
81.58ns   1.09V      1.595V     821mV
145.1ns   1.016V     1.345V     804.6mV
249.2ns   1.005V     1.245V     804.2mV
[Falling Waveform]
R_fixture= 50.000000
V_fixture= 0.0
V_fixture_min= 0.0
V_fixture_max= 0.0
|time   V(typ)   V(min)   V(max)
0s        1.369V     608.5mV    1.851V
1.061ns   1.369V     608.4mV    1.821V
1.261ns   1.369V     608.4mV    1.54V
1.682ns   1.24V      608.2mV    389.9mV
1.862ns   989mV      607.9mV    153.4mV
2.142ns   527.5mV    608.1mV    45.3mV
2.503ns   136.8mV    610.4mV    13.07mV
2.983ns   19.72mV    585.1mV    4.286mV
4.645ns   1.241mV    60.56mV    757.2uV
9.97ns    1.441uV    362.2nV    16.22uV
